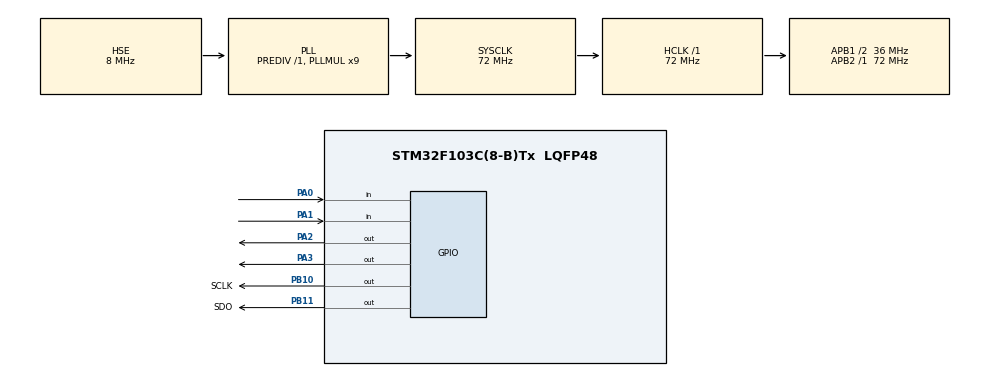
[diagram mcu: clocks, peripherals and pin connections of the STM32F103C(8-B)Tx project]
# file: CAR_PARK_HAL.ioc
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Mcu.Family=STM32F1
Mcu.Name=STM32F103C(8-B)Tx
Mcu.Package=LQFP48
NVIC.PriorityGroup=NVIC_PRIORITYGROUP_4
PA0-WKUP.Signal=GPIO_Input
PA1.Signal=GPIO_Input
PA2.Signal=GPIO_Output
PA3.Signal=GPIO_Output
PB10.GPIO_Label=SCLK
PB10.Signal=GPIO_Output
PB11.GPIO_Label=SDO
PB11.Signal=GPIO_Output
PC14-OSC32_IN.Mode=LSE-External-Oscillator
PC14-OSC32_IN.Signal=RCC_OSC32_IN
PC15-OSC32_OUT.Mode=LSE-External-Oscillator
PC15-OSC32_OUT.Signal=RCC_OSC32_OUT
PD0-OSC_IN.Mode=HSE-External-Oscillator
PD0-OSC_IN.Signal=RCC_OSC_IN
PD1-OSC_OUT.Mode=HSE-External-Oscillator
PD1-OSC_OUT.Signal=RCC_OSC_OUT
ProjectManager.HeapSize=0x200
ProjectManager.StackSize=0x400
ProjectManager.TargetToolchain=MDK-ARM V5.32
RCC.AHBFreq_Value=72000000
RCC.APB1CLKDivider=RCC_HCLK_DIV2
RCC.APB1Freq_Value=36000000
RCC.APB1TimFreq_Value=72000000
RCC.APB2Freq_Value=72000000
RCC.APB2TimFreq_Value=72000000
RCC.HCLKFreq_Value=72000000
RCC.PLLMUL=RCC_PLL_MUL9
RCC.PLLSourceVirtual=RCC_PLLSOURCE_HSE
RCC.SYSCLKFreq_VALUE=72000000
RCC.SYSCLKSource=RCC_SYSCLKSOURCE_PLLCLK
RCC.USBFreq_Value=72000000
VP_SYS_VS_ND.Mode=No_Debug
board=custom

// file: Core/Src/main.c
/* USER CODE BEGIN Header */
/**
  ******************************************************************************
  * @file           : main.c
  * @brief          : Main program body
  ******************************************************************************
  * @attention
  *
  * Copyright (c) 2024 STMicroelectronics.
  * All rights reserved.
  *
  * This software is licensed under terms that can be found in the LICENSE file
  * in the root directory of this software component.
  * If no LICENSE file comes with this software, it is provided AS-IS.
  *
  ******************************************************************************
  */
/* USER CODE END Header */
#include "main.h"

/* USER CODE BEGIN Includes */
#include "TM1637.h"
#include "Parking.h"
/* USER CODE END Includes */

/* USER CODE BEGIN PD */
#define MAX_SPACES 200
volatile int available_spaces = 0;  // Start with empty parking spaces
int brightness = 3;
#define GREEN_LED GPIO_PIN_2   // Green LED for entry indication
#define RED_LED   GPIO_PIN_3   // Red LED for exit indication
#define LED_PORT  GPIOA        // Port for LEDs
/* USER CODE END PD */

void SystemClock_Config(void);
static void MX_GPIO_Init(void);

int main(void)
{

  /* MCU Configuration--------------------------------------------------------*/

  /* Reset of all peripherals, Initializes the Flash interface and the Systick. */
  HAL_Init();

  /* Configure the system clock */
  SystemClock_Config();

  /* Initialize all configured peripherals */
  MX_GPIO_Init();
  /* USER CODE BEGIN 2 */
  Display_Startup(brightness);
  /* USER CODE END 2 */

  /* Infinite loop */
  while (1)
  {
    /* USER CODE BEGIN 3 */
    Display_FULL(brightness);
    Display_Number(available_spaces, brightness);
    Car_Entry();
    Car_Exit();
  /* USER CODE END 3 */
}}

void SystemClock_Config(void)
{
  RCC_OscInitTypeDef RCC_OscInitStruct = {0};
  RCC_ClkInitTypeDef RCC_ClkInitStruct = {0};

  /** Initializes the RCC Oscillators according to the specified parameters
  * in the RCC_OscInitTypeDef structure.
  */
  RCC_OscInitStruct.OscillatorType = RCC_OSCILLATORTYPE_HSE;
  RCC_OscInitStruct.HSEState = RCC_HSE_ON;
  RCC_OscInitStruct.HSEPredivValue = RCC_HSE_PREDIV_DIV1;
  RCC_OscInitStruct.HSIState = RCC_HSI_ON;
  RCC_OscInitStruct.PLL.PLLState = RCC_PLL_ON;
  RCC_OscInitStruct.PLL.PLLSource = RCC_PLLSOURCE_HSE;
  RCC_OscInitStruct.PLL.PLLMUL = RCC_PLL_MUL9;
  if (HAL_RCC_OscConfig(&RCC_OscInitStruct) != HAL_OK)
  {
    Error_Handler();
  }

  /** Initializes the CPU, AHB and APB buses clocks
  */
  RCC_ClkInitStruct.ClockType = RCC_CLOCKTYPE_HCLK|RCC_CLOCKTYPE_SYSCLK
                              |RCC_CLOCKTYPE_PCLK1|RCC_CLOCKTYPE_PCLK2;
  RCC_ClkInitStruct.SYSCLKSource = RCC_SYSCLKSOURCE_PLLCLK;
  RCC_ClkInitStruct.AHBCLKDivider = RCC_SYSCLK_DIV1;
  RCC_ClkInitStruct.APB1CLKDivider = RCC_HCLK_DIV2;
  RCC_ClkInitStruct.APB2CLKDivider = RCC_HCLK_DIV1;

  if (HAL_RCC_ClockConfig(&RCC_ClkInitStruct, FLASH_LATENCY_2) != HAL_OK)
  {
    Error_Handler();
  }
}

static void MX_GPIO_Init(void)
{
  GPIO_InitTypeDef GPIO_InitStruct = {0};

  /* GPIO Ports Clock Enable */
  __HAL_RCC_GPIOC_CLK_ENABLE();
  __HAL_RCC_GPIOD_CLK_ENABLE();
  __HAL_RCC_GPIOA_CLK_ENABLE();
  __HAL_RCC_GPIOB_CLK_ENABLE();

  /*Configure GPIO pin Output Level */
  HAL_GPIO_WritePin(GPIOA, GPIO_PIN_2|GPIO_PIN_3, GPIO_PIN_RESET);

  /*Configure GPIO pin Output Level */
  HAL_GPIO_WritePin(GPIOB, SCLK_Pin|SDO_Pin, GPIO_PIN_RESET);

  /*Configure GPIO pins : PA0 PA1 PA11 PA12 */
  GPIO_InitStruct.Pin = GPIO_PIN_0|GPIO_PIN_1|GPIO_PIN_11|GPIO_PIN_12;
  GPIO_InitStruct.Mode = GPIO_MODE_INPUT;
  GPIO_InitStruct.Pull = GPIO_NOPULL;
  HAL_GPIO_Init(GPIOA, &GPIO_InitStruct);

  /*Configure GPIO pins : PA2 PA3 */
  GPIO_InitStruct.Pin = GPIO_PIN_2|GPIO_PIN_3;
  GPIO_InitStruct.Mode = GPIO_MODE_OUTPUT_PP;
  GPIO_InitStruct.Pull = GPIO_NOPULL;
  GPIO_InitStruct.Speed = GPIO_SPEED_FREQ_LOW;
  HAL_GPIO_Init(GPIOA, &GPIO_InitStruct);

  /*Configure GPIO pins : SCLK_Pin SDO_Pin */
  GPIO_InitStruct.Pin = SCLK_Pin|SDO_Pin;
  GPIO_InitStruct.Mode = GPIO_MODE_OUTPUT_PP;
  GPIO_InitStruct.Pull = GPIO_NOPULL;
  GPIO_InitStruct.Speed = GPIO_SPEED_FREQ_LOW;
  HAL_GPIO_Init(GPIOB, &GPIO_InitStruct);

}

void Error_Handler(void)
{
  __disable_irq();
  while (1)
  {
  }
}
